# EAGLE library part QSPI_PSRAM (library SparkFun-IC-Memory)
QSPI PSRAM Quad-SPI PSRAM chips provide additional memory and are often highly standardized Example Parts LY68L6400SLIT

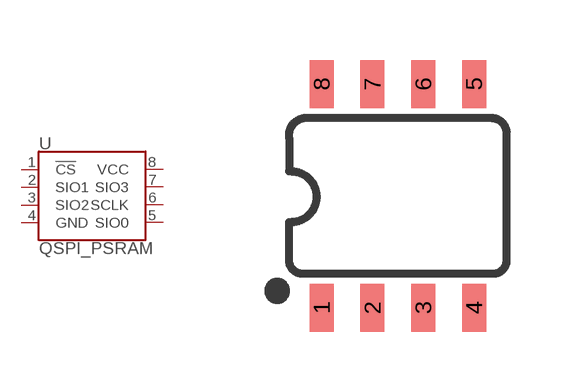
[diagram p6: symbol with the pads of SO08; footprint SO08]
Designator prefix U

## QSPI_PSRAMSO08  [SO08]
1  !CS
2  SIO1
3  SIO2
4  GND
5  SIO0
6  SCLK
7  SIO3
8  VCC

## Footprint SO08 (pad centres in mm)
SOIC, 0.15 inch width
smd 0.6 x 1.2: 1 -1.905,-2.8; 2 -0.635,-2.8; 3 0.635,-2.8; 4 1.905,-2.8; 5 1.905,2.8; 6 0.635,2.8; 7 -0.635,2.8; 8 -1.905,2.8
